One B-rep face of a CAD part: STEP entity #555.
In plain terms, the planar face has unit normal (0, 1, 0).
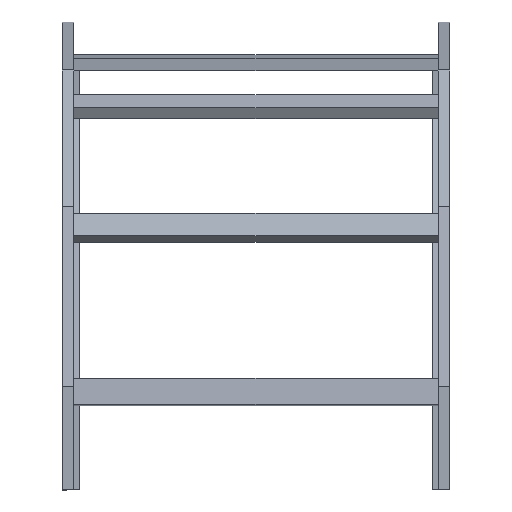
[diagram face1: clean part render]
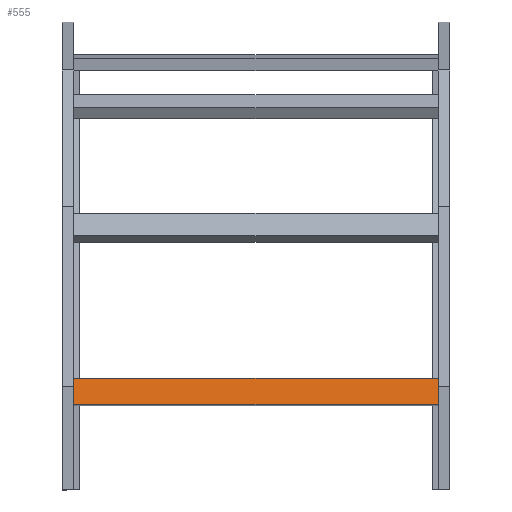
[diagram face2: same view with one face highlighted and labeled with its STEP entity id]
Its self-contained STEP definition (entity closure, numbers rounded to 3 decimals):
#50 = VERTEX_POINT ( 'NONE', #548 ) ;
#67 = ORIENTED_EDGE ( 'NONE', *, *, #609, .F. ) ;
#103 = EDGE_CURVE ( 'NONE', #578, #1815, #582, .T. ) ;
#131 = DIRECTION ( 'NONE',  ( -1., 0., 0. ) ) ;
#154 = DIRECTION ( 'NONE',  ( -1., 0., 0. ) ) ;
#289 = CARTESIAN_POINT ( 'NONE',  ( 298., 20., -20.25 ) ) ;
#296 = CARTESIAN_POINT ( 'NONE',  ( 298., 20., 20.25 ) ) ;
#478 = CARTESIAN_POINT ( 'NONE',  ( -298., 20., 20.25 ) ) ;
#501 = ORIENTED_EDGE ( 'NONE', *, *, #1775, .T. ) ;
#534 = EDGE_LOOP ( 'NONE', ( #501, #67, #1357, #586 ) ) ;
#541 = VECTOR ( 'NONE', #1228, 1000. ) ;
#548 = CARTESIAN_POINT ( 'NONE',  ( -298., 20., 20.25 ) ) ;
#555 = ADVANCED_FACE ( 'NONE', ( #994 ), #1759, .F. ) ;
#578 = VERTEX_POINT ( 'NONE', #1388 ) ;
#582 = LINE ( 'NONE', #289, #949 ) ;
#586 = ORIENTED_EDGE ( 'NONE', *, *, #103, .T. ) ;
#598 = CARTESIAN_POINT ( 'NONE',  ( 298., 20., 20.25 ) ) ;
#609 = EDGE_CURVE ( 'NONE', #1655, #50, #865, .T. ) ;
#610 = CARTESIAN_POINT ( 'NONE',  ( 298., 20., 20.25 ) ) ;
#619 = LINE ( 'NONE', #478, #541 ) ;
#728 = CARTESIAN_POINT ( 'NONE',  ( 298., 20., 20.25 ) ) ;
#865 = LINE ( 'NONE', #296, #1071 ) ;
#889 = AXIS2_PLACEMENT_3D ( 'NONE', #598, #1162, #1296 ) ;
#901 = DIRECTION ( 'NONE',  ( 0., 0., 1. ) ) ;
#949 = VECTOR ( 'NONE', #154, 1000. ) ;
#994 = FACE_OUTER_BOUND ( 'NONE', #534, .T. ) ;
#1071 = VECTOR ( 'NONE', #131, 1000. ) ;
#1083 = CARTESIAN_POINT ( 'NONE',  ( -298., 20., -20.25 ) ) ;
#1162 = DIRECTION ( 'NONE',  ( 0., -1., 0. ) ) ;
#1228 = DIRECTION ( 'NONE',  ( 0., 0., 1. ) ) ;
#1296 = DIRECTION ( 'NONE',  ( 0., 0., -1. ) ) ;
#1334 = LINE ( 'NONE', #610, #1765 ) ;
#1357 = ORIENTED_EDGE ( 'NONE', *, *, #1674, .F. ) ;
#1388 = CARTESIAN_POINT ( 'NONE',  ( 298., 20., -20.25 ) ) ;
#1655 = VERTEX_POINT ( 'NONE', #728 ) ;
#1674 = EDGE_CURVE ( 'NONE', #578, #1655, #1334, .T. ) ;
#1759 = PLANE ( 'NONE',  #889 ) ;
#1765 = VECTOR ( 'NONE', #901, 1000. ) ;
#1775 = EDGE_CURVE ( 'NONE', #1815, #50, #619, .T. ) ;
#1815 = VERTEX_POINT ( 'NONE', #1083 ) ;
